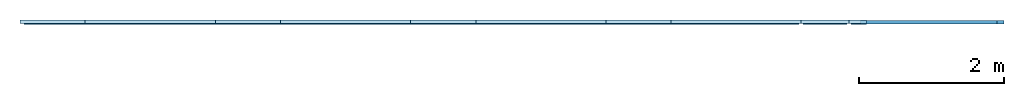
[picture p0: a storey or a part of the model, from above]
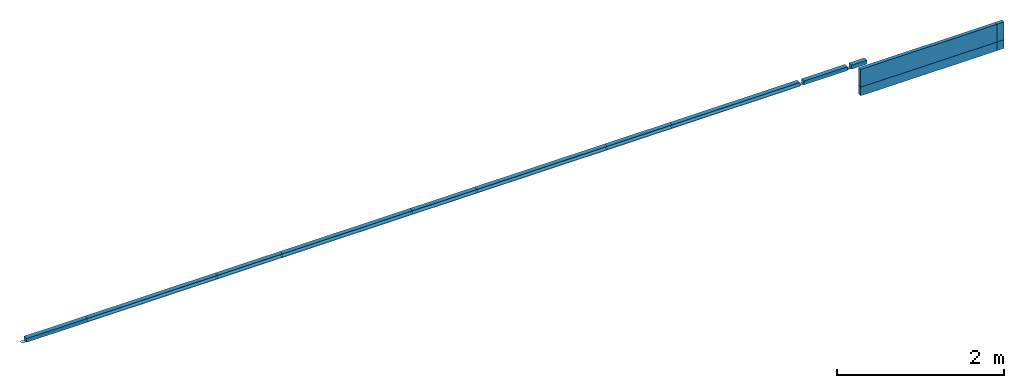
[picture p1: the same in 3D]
Properties of the parts of a building model (IFC2X3), part 1 of 2

# File
Description: ViewDefinition [CoordinationView]
File name: VA006-350-201.1.IFC (Edited by Naviate Simple BIM 2022 version 6)
Time: 2026-03-20T14:24:25+01:00
Written by: ODA SDAI 22.12
Made in: Autodesk Revit 23.1.90.15 (ENU) - IFC 23.3.1.0

# IfcProject
LongName: Trondheim Lufthavn Værnes; Phase: TU 2013

# IfcSite, Default
RefLatitude: 59, 54, 57, 601318; RefLongitude: 10, 44, 59, 999999; RefElevation: 0 mm
Identity Data - Workset: Project Info
Text - 01_Modellfil: va006-a-220-1-0001.rvt
Data - Ideate BIMLink: <?xml version="1.0" encoding="utf-8"?><application version="3"> <links> <link> <name>Casework Types</name> <description></description> <elements>CaseworkTypes</elements> <phase>Fase 2</phase> <phase_filter>None</phase_filter> <properties> <property> <name>Id</name> <lookup_1_type></lookup_1_type> <lookup_1_id></lookup_1_id> <type>BUILT_IN_PARAMETER</type> <id>ID_PARAM</id> </property> <property> <name>Family Name</name> <lookup_1_type></lookup_1_type> <lookup_1_id></lookup_1_id> <type>CALCULATED_PROPERTY</type> <id>FamilyName</id> </property> <property> <name>Type Name</name> <lookup_1_type></lookup_1_type> <lookup_1_id></lookup_1_id> <type>CALCULATED_PROPERTY</type> <id>TypeName</id> </property> </properties> </link> <link> <name>Window Types</name> <description></description> <elements>WindowTypes</elements> <phase>Fase 2</phase> <phase_filter>None</phase_filter> <properties> <property> <name>Id</name> <lookup_1_type></lookup_1_type> <lookup_1_id></lookup_1_id> <type>BUILT_IN_PARAMETER</type> <id>ID_PARAM</id> </property> <property> <name>Family Name</name> <lookup_1_type></lookup_1_type> <lookup_1_id></lookup_1_id> <type>CALCULATED_PROPERTY</type> <id>FamilyName</id> </property> <property> <name>Type Name</name> <lookup_1_type></lookup_1_type> <lookup_1_id></lookup_1_id> <type>CALCULATED_PROPERTY</type> <id>TypeName</id> </property> </properties> </link> <link> <name>Wall Types</name> <description></description> <elements>WallTypes</elements> <phase>Fase 1</phase> <phase_filter>Show Complete</phase_filter> <properties> <property> <name>Id</name> <lookup_1_type></lookup_1_type> <lookup_1_id></lookup_1_id> <type>BUILT_IN_PARAMETER</type> <id>ID_PARAM</id> </property> <property> <name>Family Name</name> <lookup_1_type></lookup_1_type> <lookup_1_id></lookup_1_id> <type>BUILT_IN_PARAMETER</type> <id>SYMBOL_FAMILY_NAME_PARAM</id> </property> <property> <name>Type Name</name> <lookup_1_type></lookup_1_type> <lookup_1_id></lookup_1_id> <type>CALCULATED_PROPERTY</type> <id>TypeName</id> </property> </properties> </link> <link> <name>Structural Framing Types</name> <description></description> <elements>StructuralFramingTypes</elements> <phase>Fase 2</phase> <phase_filter>None</phase_filter> <properties> <property> <name>Id</name> <lookup_1_type></lookup_1_type> <lookup_1_id></lookup_1_id> <type>BUILT_IN_PARAMETER</type> <id>ID_PARAM</id> </property> <property> <name>Family Name</name> <lookup_1_type></lookup_1_type> <lookup_1_id></lookup_1_id> <type>CALCULATED_PROPERTY</type> <id>FamilyName</id> </property> <property> <name>Type Name</name> <lookup_1_type></lookup_1_type> <lookup_1_id></lookup_1_id> <type>CALCULATED_PROPERTY</type> <id>TypeName</id> </property> </properties> </link> <link> <name>Structural Foundation Types</name> <description></description> <elements>StructuralFoundationTypes</elements> <phase>Fase 2</phase> <phase_filter>None</phase_filter> <properties> <property> <name>Id</name> <lookup_1_type></lookup_1_type> <lookup_1_id></lookup_1_id> <type>BUILT_IN_PARAMETER</type> <id>ID_PARAM</id> </property> <property> <name>Family Name</name> <lookup_1_type></lookup_1_type> <lookup_1_id></lookup_1_id> <type>CALCULATED_PROPERTY</type> <id>FamilyName</id> </property> <property> <name>Type Name</name> <lookup_1_type></lookup_1_type> <lookup_1_id></lookup_1_id> <type>CALCULATED_PROPERTY</type> <id>TypeName</id> </property> </properties> </link> <link> <name>Structural Column Types</name> <description></description> <elements>StructuralColumnTypes</elements> <phase>Fase 2</phase> <phase_filter>None</phase_filter> <properties> <property> <name>Id</name> <lookup_1_type></lookup_1_type> <lookup_1_id></lookup_1_id> <type>BUILT_IN_PARAMETER</type> <id>ID_PARAM</id> </property> <property> <name>Family Name</name> <lookup_1_type></lookup_1_type> <lookup_1_id></lookup_1_id> <type>CALCULATED_PROPERTY</type> <id>FamilyName</id> </property> <property> <name>Type Name</name> <lookup_1_type></lookup_1_type> <lookup_1_id></lookup_1_id> <type>CALCULATED_PROPERTY</type> <id>TypeName</id> </property> </properties> </link> <link> <name>Stair Types</name> <description></description> <elements>StairTypes</elements> <phase>Fase 2</phase> <phase_filter>None</phase_filter> <properties> <property> <name>Id</name> <lookup_1_type></lookup_1_type> <lookup_1_id></lookup_1_id> <type>BUILT_IN_PARAMETER</type> <id>ID_PARAM</id> </property> <property> <name>Family Name</name> <lookup_1_type></lookup_1_type> <lookup_1_id></lookup_1_id> <type>BUILT_IN_PARAMETER</type> <id>ALL_MODEL_FAMILY_NAME</id> </property> <property> <name>Type Name</name> <lookup_1_type></lookup_1_type> <lookup_1_id></lookup_1_id> <type>CALCULATED_PROPERTY</type> <id>TypeName</id> </property> </properties> </link> <link> <name>Specialty Equipment Types</name> <description></description> <elements>SpecialtyEquipmentTypes</elements> <phase>Fase 2</phase> <phase_filter>None</phase_filter> <properties> <property> <name>Id</name> <lookup_1_type></lookup_1_type> <lookup_1_id></lookup_1_id> <type>BUILT_IN_PARAMETER</type> <id>ID_PARAM</id> </property> <property> <name>Family Name</name> <lookup_1_type></lookup_1_type> <lookup_1_id></lookup_1_id> <type>CALCULATED_PROPERTY</type> <id>FamilyName</id> </property> <property> <name>Type Name</name> <lookup_1_type></lookup_1_type> <lookup_1_id></lookup_1_id> <type>CALCULATED_PROPERTY</type> <id>TypeName</id> </property> </properties> </link> <link> <name>Roof Types</name> <description></description> <elements>RoofTypes</elements> <phase>Fase 2</phase> <phase_filter>None</phase_filter> <properties> <property> <name>Id</name> <lookup_1_type></lookup_1_type> <lookup_1_id></lookup_1_id> <type>BUILT_IN_PARAMETER</type> <id>ID_PARAM</id> </property> <property> <name>Family Name</name> <lookup_1_type></lookup_1_type> <lookup_1_id></lookup_1_id> <type>BUILT_IN_PARAMETER</type> <id>ALL_MODEL_FAMILY_NAME</id> </property> <property> <name>Type Name</name> <lookup_1_type></lookup_1_type> <lookup_1_id></lookup_1_id> <type>CALCULATED_PROPERTY</type> <id>TypeName</id> </property> </properties> </link> <link> <name>Ramp Types</name> <description></description> <elements>RampTypes</elements> <phase>Fase 2</phase> <phase_filter>None</phase_filter> <properties> <property> <name>Id</name> <lookup_1_type></lookup_1_type> <lookup_1_id></lookup_1_id> <type>BUILT_IN_PARAMETER</type> <id>ID_PARAM</id> </property> <property> <name>Family Name</name> <lookup_1_type></lookup_1_type> <lookup_1_id></lookup_1_id> <type>BUILT_IN_PARAMETER</type> <id>ALL_MODEL_FAMILY_NAME</id> </property> <property> <name>Type Name</name> <lookup_1_type></lookup_1_type> <lookup_1_id></lookup_1_id> <type>CALCULATED_PROPERTY</type> <id>TypeName</id> </property> </properties> </link> <link> <name>Railing Types</name> <description></description> <elements>RailingTypes</elements> <phase>Fase 2</phase> <phase_filter>None</phase_filter> <properties> <property> <name>Id</name> <lookup_1_type></lookup_1_type> <lookup_1_id></lookup_1_id> <type>BUILT_IN_PARAMETER</type> <id>ID_PARAM</id> </property> <property> <name>Family Name</name> <lookup_1_type></lookup_1_type> <lookup_1_id></lookup_1_id> <type>BUILT_IN_PARAMETER</type> <id>ALL_MODEL_FAMILY_NAME</id> </property> <property> <name>Type Name</name> <lookup_1_type></lookup_1_type> <lookup_1_id></lookup_1_id> <type>CALCULATED_PROPERTY</type> <id>TypeName</id> </property> </properties> </link> <link> <name>Profile Types</name> <description></description> <elements>ProfileTypes</elements> <phase>Fase 2</phase> <phase_filter>None</phase_filter> <properties> <property> <name>Id</name> <lookup_1_type></lookup_1_type> <lookup_1_id></lookup_1_id> <type>BUILT_IN_PARAMETER</type> <id>ID_PARAM</id> </property> <property> <name>Family Name</name> <lookup_1_type></lookup_1_type> <lookup_1_id></lookup_1_id> <type>BUILT_IN_PARAMETER</type> <id>ALL_MODEL_FAMILY_NAME</id> </property> <property> <name>Type Name</name> <lookup_1_type></lookup_1_type> <lookup_1_id></lookup_1_id> <type>CALCULATED_PROPERTY</type> <id>TypeName</id> </property> </properties> </link> <link> <name>Plumbing Fixture Types</name> <description></description> <elements>PlumbingFixtureTypes</elements> <phase>Fase 2</phase> <phase_filter>None</phase_filter> <properties> <property> <name>Id</name> <lookup_1_type></lookup_1_type> <lookup_1_id></lookup_1_id> <type>BUILT_IN_PARAMETER</type> <id>ID_PARAM</id> </property> <property> <name>Family Name</name> <lookup_1_type></lookup_1_type> <lookup_1_id></lookup_1_id> <type>CALCULATED_PROPERTY</type> <id>FamilyName</id> </property> <property> <name>Type Name</name> <lookup_1_type></lookup_1_type> <lookup_1_id></lookup_1_id> <type>CALCULATED_PROPERTY</type> <id>TypeName</id> </property> </properties> </link> <link> <name>Mechanical Equipment Types</name> <description></description> <elements>MechanicalEquipmentTypes</elements> <phase>Fase 2</phase> <phase_filter>None</phase_filter> <properties> <property> <name>Id</name> <lookup_1_type></lookup_1_type> <lookup_1_id></lookup_1_id> <type>BUILT_IN_PARAMETER</type> <id>ID_PARAM</id> </property> <property> <name>Family Name</name> <lookup_1_type></lookup_1_type> <lookup_1_id></lookup_1_id> <type>CALCULATED_PROPERTY</type> <id>FamilyName</id> </property> <property> <name>Type Name</name> <lookup_1_type></lookup_1_type> <lookup_1_id></lookup_1_id> <type>CALCULATED_PROPERTY</type> <id>TypeName</id> </property> </properties> </link> <link> <name>Mass Types</name> <description></description> <elements>MassTypes</elements> <phase>Fase 2</phase> <phase_filter>None</phase_filter> <properties> <property> <name>Id</name> <lookup_1_type></lookup_1_type> <lookup_1_id></lookup_1_id> <type>BUILT_IN_PARAMETER</type> <id>ID_PARAM</id> </property> <property> <name>Family Name</name> <lookup_1_type></lookup_1_type> <lookup_1_id></lookup_1_id> <type>CALCULATED_PROPERTY</type> <id>FamilyName</id> </property> <property> <name>Type Name</name> <lookup_1_type></lookup_1_type> <lookup_1_id></lookup_1_id> <type>CALCULATED_PROPERTY</type> <id>TypeName</id> </property> </properties> </link> <link> <name>Generic Model Types</name> <description></description> <elements>GenericModelTypes</elements> <phase>Fase 2</phase> <phase_filter>None</phase_filter> <properties> <property> <name>Id</name> <lookup_1_type></lookup_1_type> <lookup_1_id></lookup_1_id> <type>BUILT_IN_PARAMETER</type> <id>ID_PARAM</id> </property> <property> <name>Family Name</name> <lookup_1_type></lookup_1_type> <lookup_1_id></lookup_1_id> <type>CALCULATED_PROPERTY</type> <id>FamilyName</id> </property> <property> <name>Type Name</name> <lookup_1_type></lookup_1_type> <lookup_1_id></lookup_1_id> <type>CALCULATED_PROPERTY</type> <id>TypeName</id> </property> </properties> </link> <link> <name>Column Types</name> <description></description> <elements>ColumnTypes</elements> <phase>Fase 2</phase> <phase_filter>None</phase_filter> <properties> <property> <name>Id</name> <lookup_1_type></lookup_1_type> <lookup_1_id></lookup_1_id> <type>BUILT_IN_PARAMETER</type> <id>ID_PARAM</id> </property> <property> <name>Family Name</name> <lookup_1_type></lookup_1_type> <lookup_1_id></lookup_1_id> <type>CALCULATED_PROPERTY</type> <id>FamilyName</id> </property> <property> <name>Type Name</name> <lookup_1_type></lookup_1_type> <lookup_1_id></lookup_1_id> <type>CALCULATED_PROPERTY</type> <id>TypeName</id> </property> </properties> </link> <link> <name>Columns</name> <description></description> <elements>ColumnInstances</elements> <phase>Fase 2</phase> <phase_filter>None</phase_filter> <properties> <property> <name>Id</name> <lookup_1_type></lookup_1_type> <lookup_1_id></lookup_1_id> <type>BUILT_IN_PARAMETER</type> <id>ID_PARAM</id> </property> </properties> </link> <link> <name>Door Types</name> <description></description> <elements>DoorTypes</elements> <phase>Fase 2</phase> <phase_filter>None</phase_filter> <properties> <property> <name>Id</name> <lookup_1_type></lookup_1_type> <lookup_1_id></lookup_1_id> <type>BUILT_IN_PARAMETER</type> <id>ID_PARAM</id> </property> <property> <name>Family Name</name> <lookup_1_type></lookup_1_type> <lookup_1_id></lookup_1_id> <type>CALCULATED_PROPERTY</type> <id>FamilyName</id> </property> <property> <name>Type Name</name> <lookup_1_type></lookup_1_type> <lookup_1_id></lookup_1_id> <type>CALCULATED_PROPERTY</type> <id>TypeName</id> </property> </properties> </link> <link> <name>Door Types 2</name> <description></description> <elements>DoorTypes</elements> <phase>Fase 1</phase> <phase_filter>Show Complete</phase_filter> <properties> <property> <name>Id</name> <lookup_1_type></lookup_1_type> <lookup_1_id></lookup_1_id> <type>BUILT_IN_PARAMETER</type> <id>ID_PARAM</id> </property> <property> <name>Family Name</name> <lookup_1_type></lookup_1_type> <lookup_1_id></lookup_1_id> <type>CALCULATED_PROPERTY</type> <id>FamilyName</id> </property> <property> <name>Type Name</name> <lookup_1_type></lookup_1_type> <lookup_1_id></lookup_1_id> <type>CALCULATED_PROPERTY</type> <id>TypeName</id> </property> </properties> </link> <link> <name>Ceiling Types</name> <description></description> <elements>CeilingTypes</elements> <phase>Fase 2</phase> <phase_filter>None</phase_filter> <properties> <property> <name>Id</name> <lookup_1_type></lookup_1_type> <lookup_1_id></lookup_1_id> <type>BUILT_IN_PARAMETER</type> <id>ID_PARAM</id> </property> <property> <name>Family Name</name> <lookup_1_type></lookup_1_type> <lookup_1_id></lookup_1_id> <type>BUILT_IN_PARAMETER</type> <id>ALL_MODEL_FAMILY_NAME</id> </property> <property> <name>Type Name</name> <lookup_1_type></lookup_1_type> <lookup_1_id></lookup_1_id> <type>CALCULATED_PROPERTY</type> <id>TypeName</id> </property> </properties> </link> <link> <name>Ceilings</name> <description></description> <elements>CeilingInstances</elements> <phase>Fase 2</phase> <phase_filter>None</phase_filter> <properties> <property> <name>Id</name> <lookup_1_type></lookup_1_type> <lookup_1_id></lookup_1_id> <type>BUILT_IN_PARAMETER</type> <id>ID_PARAM</id> </property> <property> <name>Family Name</name> <lookup_1_type>BUILT_IN_PARAMETER</lookup_1_type> <lookup_1_id>SYMBOL_ID_PARAM</lookup_1_id> <type>BUILT_IN_PARAMETER</type> <id>ALL_MODEL_FAMILY_NAME</id> </property> <property> <name>Type Name</name> <lookup_1_type>BUILT_IN_PARAMETER</lookup_1_type> <lookup_1_id>SYMBOL_ID_PARAM</lookup_1_id> <type>CALCULATED_PROPERTY</type> <id>TypeName</id> </property> </properties> </link> <link> <name>Furniture Types</name> <description></description> <elements>FurnitureTypes</elements> <phase>Fase 2</phase> <phase_filter>None</phase_filter> <properties> <property> <name>Id</name> <lookup_1_type></lookup_1_type> <lookup_1_id></lookup_1_id> <type>BUILT_IN_PARAMETER</type> <id>ID_PARAM</id> </property> <property> <name>Family Name</name> <lookup_1_type></lookup_1_type> <lookup_1_id></lookup_1_id> <type>CALCULATED_PROPERTY</type> <id>FamilyName</id> </property> <property> <name>Type Name</name> <lookup_1_type></lookup_1_type> <lookup_1_id></lookup_1_id> <type>CALCULATED_PROPERTY</type> <id>TypeName</id> </property> </properties> </link> <link> <name>Furniture System Types</name> <description></description> <elements>FurnitureSystemTypes</elements> <phase>Fase 2</phase> <phase_filter>None</phase_filter> <properties> <property> <name>Id</name> <lookup_1_type></lookup_1_type> <lookup_1_id></lookup_1_id> <type>BUILT_IN_PARAMETER</type> <id>ID_PARAM</id> </property> <property> <name>Family Name</name> <lookup_1_type></lookup_1_type> <lookup_1_id></lookup_1_id> <type>CALCULATED_PROPERTY</type> <id>FamilyName</id> </property> <property> <name>Type Name</name> <lookup_1_type></lookup_1_type> <lookup_1_id></lookup_1_id> <type>CALCULATED_PROPERTY</type> <id>TypeName</id> </property> </properties> </link> <link> <name>Sheets</name> <description></description> <elements>Sheets</elements> <phase>Fase 1</phase> <phase_filter>None</phase_filter> <properties> <property> <name>Id</name> <lookup_1_type></lookup_1_type> <lookup_1_id></lookup_1_id> <type>BUILT_IN_PARAMETER</type> <id>ID_PARAM</id> </property> </properties> </link> <link> <name>Walls</name> <description></description> <elements>WallInstances</elements> <phase>Fase 2</phase> <phase_filter>None</phase_filter> <properties> <property> <name>Id</name> <lookup_1_type></lookup_1_type> <lookup_1_id></lookup_1_id> <type>BUILT_IN_PARAMETER</type> <id>ID_PARAM</id> </property> </properties> </link> <link> <name>Wall types all official names</name> <description></description> <elements>WallTypes</elements> <phase>Fase 1</phase> <phase_filter>None</phase_filter> <properties> <property> <name>Id</name> <lookup_1_type></lookup_1_type> <lookup_1_id></lookup_1_id> <type>BUILT_IN_PARAMETER</type> <id>ID_PARAM</id> </property> <property> <name>Family Name</name> <lookup_1_type></lookup_1_type> <lookup_1_id></lookup_1_id> <type>BUILT_IN_PARAMETER</type> <id>ALL_MODEL_FAMILY_NAME</id> </property> <property> <name>Type Name</name> <lookup_1_type></lookup_1_type> <lookup_1_id></lookup_1_id> <type>CALCULATED_PROPERTY</type> <id>TypeName</id> </property> </properties> </link> <link> <name>test</name> <description></description> <elements>WallTypes</elements> <phase>Fase 1</phase> <phase_filter>None</phase_filter> <properties> <property> <name>Id</name> <lookup_1_type></lookup_1_type> <lookup_1_id></lookup_1_id> <type>BUILT_IN_PARAMETER</type> <id>ID_PARAM</id> </property> <property> <name>Family Name</name> <lookup_1_type></lookup_1_type> <lookup_1_id></lookup_1_id> <type>BUILT_IN_PARAMETER</type> <id>ALL_MODEL_FAMILY_NAME</id> </property> <property> <name>Type Name</name> <lookup_1_type></lookup_1_type> <lookup_1_id></lookup_1_id> <type>CALCULATED_PROPERTY</type> <id>TypeName</id> </property> </properties> </link> </links></application>
Other - RIE, firma: RAMBØLL AS; Project Status: TU 2013; Saksbehandler: MR; Project Address: Skriv adresse her; Category: Project Information; Prosjektansvarlig: TILBUD E203 TETT BYGG; RIV, telefon: +47 7310 6200; RIB, telefon: +47 7289 3750; Project Name: Trondheim Lufthavn Værnes; RIV, firma: MULTICONSULT AS; RIB, firma: NORCONSULT; RIE, telefon: +47 7389 1000

# IfcBuilding
Pset_BuildingCommon - NumberOfStoreys: 7
Identity Data - Workset: Project Info
Text - 01_Modellfil: va006-a-220-1-0001.rvt
Data - Ideate BIMLink: <?xml version="1.0" encoding="utf-8"?><application version="3"> <links> <link> <name>Casework Types</name> <description></description> <elements>CaseworkTypes</elements> <phase>Fase 2</phase> <phase_filter>None</phase_filter> <properties> <property> <name>Id</name> <lookup_1_type></lookup_1_type> <lookup_1_id></lookup_1_id> <type>BUILT_IN_PARAMETER</type> <id>ID_PARAM</id> </property> <property> <name>Family Name</name> <lookup_1_type></lookup_1_type> <lookup_1_id></lookup_1_id> <type>CALCULATED_PROPERTY</type> <id>FamilyName</id> </property> <property> <name>Type Name</name> <lookup_1_type></lookup_1_type> <lookup_1_id></lookup_1_id> <type>CALCULATED_PROPERTY</type> <id>TypeName</id> </property> </properties> </link> <link> <name>Window Types</name> <description></description> <elements>WindowTypes</elements> <phase>Fase 2</phase> <phase_filter>None</phase_filter> <properties> <property> <name>Id</name> <lookup_1_type></lookup_1_type> <lookup_1_id></lookup_1_id> <type>BUILT_IN_PARAMETER</type> <id>ID_PARAM</id> </property> <property> <name>Family Name</name> <lookup_1_type></lookup_1_type> <lookup_1_id></lookup_1_id> <type>CALCULATED_PROPERTY</type> <id>FamilyName</id> </property> <property> <name>Type Name</name> <lookup_1_type></lookup_1_type> <lookup_1_id></lookup_1_id> <type>CALCULATED_PROPERTY</type> <id>TypeName</id> </property> </properties> </link> <link> <name>Wall Types</name> <description></description> <elements>WallTypes</elements> <phase>Fase 1</phase> <phase_filter>Show Complete</phase_filter> <properties> <property> <name>Id</name> <lookup_1_type></lookup_1_type> <lookup_1_id></lookup_1_id> <type>BUILT_IN_PARAMETER</type> <id>ID_PARAM</id> </property> <property> <name>Family Name</name> <lookup_1_type></lookup_1_type> <lookup_1_id></lookup_1_id> <type>BUILT_IN_PARAMETER</type> <id>SYMBOL_FAMILY_NAME_PARAM</id> </property> <property> <name>Type Name</name> <lookup_1_type></lookup_1_type> <lookup_1_id></lookup_1_id> <type>CALCULATED_PROPERTY</type> <id>TypeName</id> </property> </properties> </link> <link> <name>Structural Framing Types</name> <description></description> <elements>StructuralFramingTypes</elements> <phase>Fase 2</phase> <phase_filter>None</phase_filter> <properties> <property> <name>Id</name> <lookup_1_type></lookup_1_type> <lookup_1_id></lookup_1_id> <type>BUILT_IN_PARAMETER</type> <id>ID_PARAM</id> </property> <property> <name>Family Name</name> <lookup_1_type></lookup_1_type> <lookup_1_id></lookup_1_id> <type>CALCULATED_PROPERTY</type> <id>FamilyName</id> </property> <property> <name>Type Name</name> <lookup_1_type></lookup_1_type> <lookup_1_id></lookup_1_id> <type>CALCULATED_PROPERTY</type> <id>TypeName</id> </property> </properties> </link> <link> <name>Structural Foundation Types</name> <description></description> <elements>StructuralFoundationTypes</elements> <phase>Fase 2</phase> <phase_filter>None</phase_filter> <properties> <property> <name>Id</name> <lookup_1_type></lookup_1_type> <lookup_1_id></lookup_1_id> <type>BUILT_IN_PARAMETER</type> <id>ID_PARAM</id> </property> <property> <name>Family Name</name> <lookup_1_type></lookup_1_type> <lookup_1_id></lookup_1_id> <type>CALCULATED_PROPERTY</type> <id>FamilyName</id> </property> <property> <name>Type Name</name> <lookup_1_type></lookup_1_type> <lookup_1_id></lookup_1_id> <type>CALCULATED_PROPERTY</type> <id>TypeName</id> </property> </properties> </link> <link> <name>Structural Column Types</name> <description></description> <elements>StructuralColumnTypes</elements> <phase>Fase 2</phase> <phase_filter>None</phase_filter> <properties> <property> <name>Id</name> <lookup_1_type></lookup_1_type> <lookup_1_id></lookup_1_id> <type>BUILT_IN_PARAMETER</type> <id>ID_PARAM</id> </property> <property> <name>Family Name</name> <lookup_1_type></lookup_1_type> <lookup_1_id></lookup_1_id> <type>CALCULATED_PROPERTY</type> <id>FamilyName</id> </property> <property> <name>Type Name</name> <lookup_1_type></lookup_1_type> <lookup_1_id></lookup_1_id> <type>CALCULATED_PROPERTY</type> <id>TypeName</id> </property> </properties> </link> <link> <name>Stair Types</name> <description></description> <elements>StairTypes</elements> <phase>Fase 2</phase> <phase_filter>None</phase_filter> <properties> <property> <name>Id</name> <lookup_1_type></lookup_1_type> <lookup_1_id></lookup_1_id> <type>BUILT_IN_PARAMETER</type> <id>ID_PARAM</id> </property> <property> <name>Family Name</name> <lookup_1_type></lookup_1_type> <lookup_1_id></lookup_1_id> <type>BUILT_IN_PARAMETER</type> <id>ALL_MODEL_FAMILY_NAME</id> </property> <property> <name>Type Name</name> <lookup_1_type></lookup_1_type> <lookup_1_id></lookup_1_id> <type>CALCULATED_PROPERTY</type> <id>TypeName</id> </property> </properties> </link> <link> <name>Specialty Equipment Types</name> <description></description> <elements>SpecialtyEquipmentTypes</elements> <phase>Fase 2</phase> <phase_filter>None</phase_filter> <properties> <property> <name>Id</name> <lookup_1_type></lookup_1_type> <lookup_1_id></lookup_1_id> <type>BUILT_IN_PARAMETER</type> <id>ID_PARAM</id> </property> <property> <name>Family Name</name> <lookup_1_type></lookup_1_type> <lookup_1_id></lookup_1_id> <type>CALCULATED_PROPERTY</type> <id>FamilyName</id> </property> <property> <name>Type Name</name> <lookup_1_type></lookup_1_type> <lookup_1_id></lookup_1_id> <type>CALCULATED_PROPERTY</type> <id>TypeName</id> </property> </properties> </link> <link> <name>Roof Types</name> <description></description> <elements>RoofTypes</elements> <phase>Fase 2</phase> <phase_filter>None</phase_filter> <properties> <property> <name>Id</name> <lookup_1_type></lookup_1_type> <lookup_1_id></lookup_1_id> <type>BUILT_IN_PARAMETER</type> <id>ID_PARAM</id> </property> <property> <name>Family Name</name> <lookup_1_type></lookup_1_type> <lookup_1_id></lookup_1_id> <type>BUILT_IN_PARAMETER</type> <id>ALL_MODEL_FAMILY_NAME</id> </property> <property> <name>Type Name</name> <lookup_1_type></lookup_1_type> <lookup_1_id></lookup_1_id> <type>CALCULATED_PROPERTY</type> <id>TypeName</id> </property> </properties> </link> <link> <name>Ramp Types</name> <description></description> <elements>RampTypes</elements> <phase>Fase 2</phase> <phase_filter>None</phase_filter> <properties> <property> <name>Id</name> <lookup_1_type></lookup_1_type> <lookup_1_id></lookup_1_id> <type>BUILT_IN_PARAMETER</type> <id>ID_PARAM</id> </property> <property> <name>Family Name</name> <lookup_1_type></lookup_1_type> <lookup_1_id></lookup_1_id> <type>BUILT_IN_PARAMETER</type> <id>ALL_MODEL_FAMILY_NAME</id> </property> <property> <name>Type Name</name> <lookup_1_type></lookup_1_type> <lookup_1_id></lookup_1_id> <type>CALCULATED_PROPERTY</type> <id>TypeName</id> </property> </properties> </link> <link> <name>Railing Types</name> <description></description> <elements>RailingTypes</elements> <phase>Fase 2</phase> <phase_filter>None</phase_filter> <properties> <property> <name>Id</name> <lookup_1_type></lookup_1_type> <lookup_1_id></lookup_1_id> <type>BUILT_IN_PARAMETER</type> <id>ID_PARAM</id> </property> <property> <name>Family Name</name> <lookup_1_type></lookup_1_type> <lookup_1_id></lookup_1_id> <type>BUILT_IN_PARAMETER</type> <id>ALL_MODEL_FAMILY_NAME</id> </property> <property> <name>Type Name</name> <lookup_1_type></lookup_1_type> <lookup_1_id></lookup_1_id> <type>CALCULATED_PROPERTY</type> <id>TypeName</id> </property> </properties> </link> <link> <name>Profile Types</name> <description></description> <elements>ProfileTypes</elements> <phase>Fase 2</phase> <phase_filter>None</phase_filter> <properties> <property> <name>Id</name> <lookup_1_type></lookup_1_type> <lookup_1_id></lookup_1_id> <type>BUILT_IN_PARAMETER</type> <id>ID_PARAM</id> </property> <property> <name>Family Name</name> <lookup_1_type></lookup_1_type> <lookup_1_id></lookup_1_id> <type>BUILT_IN_PARAMETER</type> <id>ALL_MODEL_FAMILY_NAME</id> </property> <property> <name>Type Name</name> <lookup_1_type></lookup_1_type> <lookup_1_id></lookup_1_id> <type>CALCULATED_PROPERTY</type> <id>TypeName</id> </property> </properties> </link> <link> <name>Plumbing Fixture Types</name> <description></description> <elements>PlumbingFixtureTypes</elements> <phase>Fase 2</phase> <phase_filter>None</phase_filter> <properties> <property> <name>Id</name> <lookup_1_type></lookup_1_type> <lookup_1_id></lookup_1_id> <type>BUILT_IN_PARAMETER</type> <id>ID_PARAM</id> </property> <property> <name>Family Name</name> <lookup_1_type></lookup_1_type> <lookup_1_id></lookup_1_id> <type>CALCULATED_PROPERTY</type> <id>FamilyName</id> </property> <property> <name>Type Name</name> <lookup_1_type></lookup_1_type> <lookup_1_id></lookup_1_id> <type>CALCULATED_PROPERTY</type> <id>TypeName</id> </property> </properties> </link> <link> <name>Mechanical Equipment Types</name> <description></description> <elements>MechanicalEquipmentTypes</elements> <phase>Fase 2</phase> <phase_filter>None</phase_filter> <properties> <property> <name>Id</name> <lookup_1_type></lookup_1_type> <lookup_1_id></lookup_1_id> <type>BUILT_IN_PARAMETER</type> <id>ID_PARAM</id> </property> <property> <name>Family Name</name> <lookup_1_type></lookup_1_type> <lookup_1_id></lookup_1_id> <type>CALCULATED_PROPERTY</type> <id>FamilyName</id> </property> <property> <name>Type Name</name> <lookup_1_type></lookup_1_type> <lookup_1_id></lookup_1_id> <type>CALCULATED_PROPERTY</type> <id>TypeName</id> </property> </properties> </link> <link> <name>Mass Types</name> <description></description> <elements>MassTypes</elements> <phase>Fase 2</phase> <phase_filter>None</phase_filter> <properties> <property> <name>Id</name> <lookup_1_type></lookup_1_type> <lookup_1_id></lookup_1_id> <type>BUILT_IN_PARAMETER</type> <id>ID_PARAM</id> </property> <property> <name>Family Name</name> <lookup_1_type></lookup_1_type> <lookup_1_id></lookup_1_id> <type>CALCULATED_PROPERTY</type> <id>FamilyName</id> </property> <property> <name>Type Name</name> <lookup_1_type></lookup_1_type> <lookup_1_id></lookup_1_id> <type>CALCULATED_PROPERTY</type> <id>TypeName</id> </property> </properties> </link> <link> <name>Generic Model Types</name> <description></description> <elements>GenericModelTypes</elements> <phase>Fase 2</phase> <phase_filter>None</phase_filter> <properties> <property> <name>Id</name> <lookup_1_type></lookup_1_type> <lookup_1_id></lookup_1_id> <type>BUILT_IN_PARAMETER</type> <id>ID_PARAM</id> </property> <property> <name>Family Name</name> <lookup_1_type></lookup_1_type> <lookup_1_id></lookup_1_id> <type>CALCULATED_PROPERTY</type> <id>FamilyName</id> </property> <property> <name>Type Name</name> <lookup_1_type></lookup_1_type> <lookup_1_id></lookup_1_id> <type>CALCULATED_PROPERTY</type> <id>TypeName</id> </property> </properties> </link> <link> <name>Column Types</name> <description></description> <elements>ColumnTypes</elements> <phase>Fase 2</phase> <phase_filter>None</phase_filter> <properties> <property> <name>Id</name> <lookup_1_type></lookup_1_type> <lookup_1_id></lookup_1_id> <type>BUILT_IN_PARAMETER</type> <id>ID_PARAM</id> </property> <property> <name>Family Name</name> <lookup_1_type></lookup_1_type> <lookup_1_id></lookup_1_id> <type>CALCULATED_PROPERTY</type> <id>FamilyName</id> </property> <property> <name>Type Name</name> <lookup_1_type></lookup_1_type> <lookup_1_id></lookup_1_id> <type>CALCULATED_PROPERTY</type> <id>TypeName</id> </property> </properties> </link> <link> <name>Columns</name> <description></description> <elements>ColumnInstances</elements> <phase>Fase 2</phase> <phase_filter>None</phase_filter> <properties> <property> <name>Id</name> <lookup_1_type></lookup_1_type> <lookup_1_id></lookup_1_id> <type>BUILT_IN_PARAMETER</type> <id>ID_PARAM</id> </property> </properties> </link> <link> <name>Door Types</name> <description></description> <elements>DoorTypes</elements> <phase>Fase 2</phase> <phase_filter>None</phase_filter> <properties> <property> <name>Id</name> <lookup_1_type></lookup_1_type> <lookup_1_id></lookup_1_id> <type>BUILT_IN_PARAMETER</type> <id>ID_PARAM</id> </property> <property> <name>Family Name</name> <lookup_1_type></lookup_1_type> <lookup_1_id></lookup_1_id> <type>CALCULATED_PROPERTY</type> <id>FamilyName</id> </property> <property> <name>Type Name</name> <lookup_1_type></lookup_1_type> <lookup_1_id></lookup_1_id> <type>CALCULATED_PROPERTY</type> <id>TypeName</id> </property> </properties> </link> <link> <name>Door Types 2</name> <description></description> <elements>DoorTypes</elements> <phase>Fase 1</phase> <phase_filter>Show Complete</phase_filter> <properties> <property> <name>Id</name> <lookup_1_type></lookup_1_type> <lookup_1_id></lookup_1_id> <type>BUILT_IN_PARAMETER</type> <id>ID_PARAM</id> </property> <property> <name>Family Name</name> <lookup_1_type></lookup_1_type> <lookup_1_id></lookup_1_id> <type>CALCULATED_PROPERTY</type> <id>FamilyName</id> </property> <property> <name>Type Name</name> <lookup_1_type></lookup_1_type> <lookup_1_id></lookup_1_id> <type>CALCULATED_PROPERTY</type> <id>TypeName</id> </property> </properties> </link> <link> <name>Ceiling Types</name> <description></description> <elements>CeilingTypes</elements> <phase>Fase 2</phase> <phase_filter>None</phase_filter> <properties> <property> <name>Id</name> <lookup_1_type></lookup_1_type> <lookup_1_id></lookup_1_id> <type>BUILT_IN_PARAMETER</type> <id>ID_PARAM</id> </property> <property> <name>Family Name</name> <lookup_1_type></lookup_1_type> <lookup_1_id></lookup_1_id> <type>BUILT_IN_PARAMETER</type> <id>ALL_MODEL_FAMILY_NAME</id> </property> <property> <name>Type Name</name> <lookup_1_type></lookup_1_type> <lookup_1_id></lookup_1_id> <type>CALCULATED_PROPERTY</type> <id>TypeName</id> </property> </properties> </link> <link> <name>Ceilings</name> <description></description> <elements>CeilingInstances</elements> <phase>Fase 2</phase> <phase_filter>None</phase_filter> <properties> <property> <name>Id</name> <lookup_1_type></lookup_1_type> <lookup_1_id></lookup_1_id> <type>BUILT_IN_PARAMETER</type> <id>ID_PARAM</id> </property> <property> <name>Family Name</name> <lookup_1_type>BUILT_IN_PARAMETER</lookup_1_type> <lookup_1_id>SYMBOL_ID_PARAM</lookup_1_id> <type>BUILT_IN_PARAMETER</type> <id>ALL_MODEL_FAMILY_NAME</id> </property> <property> <name>Type Name</name> <lookup_1_type>BUILT_IN_PARAMETER</lookup_1_type> <lookup_1_id>SYMBOL_ID_PARAM</lookup_1_id> <type>CALCULATED_PROPERTY</type> <id>TypeName</id> </property> </properties> </link> <link> <name>Furniture Types</name> <description></description> <elements>FurnitureTypes</elements> <phase>Fase 2</phase> <phase_filter>None</phase_filter> <properties> <property> <name>Id</name> <lookup_1_type></lookup_1_type> <lookup_1_id></lookup_1_id> <type>BUILT_IN_PARAMETER</type> <id>ID_PARAM</id> </property> <property> <name>Family Name</name> <lookup_1_type></lookup_1_type> <lookup_1_id></lookup_1_id> <type>CALCULATED_PROPERTY</type> <id>FamilyName</id> </property> <property> <name>Type Name</name> <lookup_1_type></lookup_1_type> <lookup_1_id></lookup_1_id> <type>CALCULATED_PROPERTY</type> <id>TypeName</id> </property> </properties> </link> <link> <name>Furniture System Types</name> <description></description> <elements>FurnitureSystemTypes</elements> <phase>Fase 2</phase> <phase_filter>None</phase_filter> <properties> <property> <name>Id</name> <lookup_1_type></lookup_1_type> <lookup_1_id></lookup_1_id> <type>BUILT_IN_PARAMETER</type> <id>ID_PARAM</id> </property> <property> <name>Family Name</name> <lookup_1_type></lookup_1_type> <lookup_1_id></lookup_1_id> <type>CALCULATED_PROPERTY</type> <id>FamilyName</id> </property> <property> <name>Type Name</name> <lookup_1_type></lookup_1_type> <lookup_1_id></lookup_1_id> <type>CALCULATED_PROPERTY</type> <id>TypeName</id> </property> </properties> </link> <link> <name>Sheets</name> <description></description> <elements>Sheets</elements> <phase>Fase 1</phase> <phase_filter>None</phase_filter> <properties> <property> <name>Id</name> <lookup_1_type></lookup_1_type> <lookup_1_id></lookup_1_id> <type>BUILT_IN_PARAMETER</type> <id>ID_PARAM</id> </property> </properties> </link> <link> <name>Walls</name> <description></description> <elements>WallInstances</elements> <phase>Fase 2</phase> <phase_filter>None</phase_filter> <properties> <property> <name>Id</name> <lookup_1_type></lookup_1_type> <lookup_1_id></lookup_1_id> <type>BUILT_IN_PARAMETER</type> <id>ID_PARAM</id> </property> </properties> </link> <link> <name>Wall types all official names</name> <description></description> <elements>WallTypes</elements> <phase>Fase 1</phase> <phase_filter>None</phase_filter> <properties> <property> <name>Id</name> <lookup_1_type></lookup_1_type> <lookup_1_id></lookup_1_id> <type>BUILT_IN_PARAMETER</type> <id>ID_PARAM</id> </property> <property> <name>Family Name</name> <lookup_1_type></lookup_1_type> <lookup_1_id></lookup_1_id> <type>BUILT_IN_PARAMETER</type> <id>ALL_MODEL_FAMILY_NAME</id> </property> <property> <name>Type Name</name> <lookup_1_type></lookup_1_type> <lookup_1_id></lookup_1_id> <type>CALCULATED_PROPERTY</type> <id>TypeName</id> </property> </properties> </link> <link> <name>test</name> <description></description> <elements>WallTypes</elements> <phase>Fase 1</phase> <phase_filter>None</phase_filter> <properties> <property> <name>Id</name> <lookup_1_type></lookup_1_type> <lookup_1_id></lookup_1_id> <type>BUILT_IN_PARAMETER</type> <id>ID_PARAM</id> </property> <property> <name>Family Name</name> <lookup_1_type></lookup_1_type> <lookup_1_id></lookup_1_id> <type>BUILT_IN_PARAMETER</type> <id>ALL_MODEL_FAMILY_NAME</id> </property> <property> <name>Type Name</name> <lookup_1_type></lookup_1_type> <lookup_1_id></lookup_1_id> <type>CALCULATED_PROPERTY</type> <id>TypeName</id> </property> </properties> </link> </links></application>
Other - RIE, firma: RAMBØLL AS; Project Status: TU 2013; Saksbehandler: MR; Project Address: Skriv adresse her; Category: Project Information; Prosjektansvarlig: TILBUD E203 TETT BYGG; RIV, telefon: +47 7310 6200; RIB, telefon: +47 7289 3750; Project Name: Trondheim Lufthavn Værnes; RIV, firma: MULTICONSULT AS; RIB, firma: NORCONSULT; RIE, telefon: +47 7389 1000

# IfcBuildingStorey: Level:JB + TC, +11.535 - TC/PIR - E1
LongName: +11.535 - TC/PIR - E1; Elevation: 11535 mm
Graphics(Type) - Line Pattern: Centre; Symbol: M_Level Head - Circle; Color: 0; Symbol at End 1 Default: yes; Symbol at End 2 Default: no; Line Weight: 4
Constraints - Elevation: 11535 mm
Identity Data - Name: +11.535 - TC/PIR - E1; Structural: no; Building Story: yes; AP3 PIR VEST: yes; Workset: Akser/Nivåer-AP3
Other - Type Id: 7724940; Type: JB + TC; Family and Type: Level: JB + TC; Category: Levels; Family: Level
Identity Data(Type) - Workset: Level Types; Type Name: JB + TC
Pset_ProductRequirements - Name: +11.535 - TC/PIR - E1; sets with these values: 2
Dimensions - Computation Height: 0 mm
Other(Type) - Category: Levels; Family Name: Level
Constraints(Type) - Elevation Base: Project Base Point

# IfcBuildingStorey: Level:TA (3)
Identity Data(Type) - Workset: Level Types; Type Name: TA
Graphics(Type) - Symbol: NSW Kote - Triangel med kote, ISO 2,5 mm (fault, do not use -DC) : NSW Kote - Triangel med kote, ISO 2,5 mm; Line Pattern: Centre; Color: 0; Symbol at End 1 Default: yes; Symbol at End 2 Default: no; Line Weight: 4
Other - Family and Type: Level: TA; Type Id: 7724934; Type: TA; Category: Levels; Family: Level
Identity Data - Structural: no; Building Story: yes; Workset: Shared Levels and Grids
Other(Type) - Category: Levels; Family Name: Level
Constraints(Type) - Elevation Base: Project Base Point
Name | LongName = Identity Data, Name | Elevation (mm) = Constraints, Elevation (mm) | Computation Height (mm) | Pset_ProductRequirements, Name | Pset_ProductRequirements, sets with these values
XX - C +10,75 TA E1 | XX - C +10,75 TA E1 | 10750 | 1200 | Pset_AirSideSystemInformation - Name: XX - C +10,75 TA E1; sets with these values: 2
XX - C +15,37 TA E2 | XX - C +15,37 TA E2 | 15370 | 1200 | XX - C +15,37 TA E2 | 2
XX - C +18,62 | XX - C +18,62 | 18620 | 0 | XX - C +18,62 | 2

# IfcCovering: Compound Ceiling:Værnes Himling H-SYS 01, Compound Ceiling:Værnes Himling H-SYS 01:18535406
In: XX - C +15,37 TA E2
Type - PredefinedType: CEILING
Type - Other - Category: Ceilings; Family Name: Compound Ceiling
Type - Construction - Thickness: 15 mm
Type - Graphics - Coarse Scale Fill Color: 0
Type - Identity Data - Type Name: Værnes Himling H-SYS 01; Workset: Ceiling Types
Type - Text - Himling Kode: H-SYS 01
Type - Analytical Properties - Roughness: 1; Absorptance: 0.1
Type - Pset_CoveringCommon - TotalThickness: 15 mm
Material: Structure - Light Gauge Steel Joist Layer 2 mm, _NSW Himlingsplate 600x600 mm 13 mm
Dimensions - Perimeter: 31225 mm; Volume: 0.569142 m3; Area: 37.9428 m2
ePset_Simplebim - Assembly Level: Leaf
ePset_LocationTool - Splitting: ORIGINAL
Constraints - Room Bounding: yes; Level: XX - C +15,37 TA E2; Height Offset From Level: 2415 mm
Other - Family: Compound Ceiling; Type: Værnes Himling H-SYS 01; Type Id: 6696750; Family and Type: Compound Ceiling: Værnes Himling H-SYS 01
Phasing - Phase Created: Som Bygget
Pset_QuantityTakeOff - Reference: Værnes Himling H-SYS 01
Pset_CoveringCommon - Reference: Værnes Himling H-SYS 01; Finish: _NSW Himlingsplate 600x600 mm;
Identity Data - TA Workset: yes; TB Workset: no; AP3 COMMUTER: no; Workset: XTB Terminal B
ePset_SimplebimBasicQuantities - Length (Simplebim): 12601.5 mm; Width (Simplebim): 3010.98 mm; Volume, net (Simplebim): 0.569142 m3; Area, largest surface, net (Simplebim): 37.9428 m2; Height (Simplebim): 15 mm

# IfcCurtainWall: Curtain Wall:V_Existing Curtain Wall, Curtain Wall:V_Existing Curtain Wall:5591690
In: XX - C +10,75 TA E1
Type - Other - Category: Walls; Family Name: Curtain Wall
Type - Construction - Function: Exterior; Automatically Embed: no; Join Condition: Not Defined
Type - Identity Data - Type Name: V_Existing Curtain Wall; Workset: Curtain Wall Types
Type - Horizontal Grid - Adjust for Mullion Size: no
Type - Vertical Grid - Adjust for Mullion Size: no
Type - Pset_CurtainWallCommon - IsExternal: yes
Phasing - Phase Created: Som Bygget
Pset_CurtainWallCommon - Reference: V_Existing Curtain Wall
ePset_Simplebim - Assembly Level: Topmost
Pset_QuantityTakeOff - Reference: V_Existing Curtain Wall
Structural - Structural Usage: Non-bearing; Structural: no
Other - Type: V_Existing Curtain Wall; Family and Type: Curtain Wall: V_Existing Curtain Wall; Type Id: 4351841; Family: Curtain Wall
Identity Data - TA Workset: yes; Workset: XTA Terminal A
Constraints - Base Constraint: XX - C +10,75 TA E1; Related to Mass: no; Base is Attached: no; Room Bounding: no; Top is Attached: no; Top Offset: 0 mm; Base Offset: 480 mm; Unconnected Height: 8190 mm
Cross-Section Definition - Cross-Section: Vertical
Dimensions - Area: 120.253 m2; Length: 33361.3 mm
Horizontal Grid - Angle: 0 deg; Offset: 0 mm; Number: 4; Justification: Beginning
Vertical Grid - Number: 4; Angle: 0 deg; Offset: 0 mm; Justification: Beginning
ePset_SimplebimBasicQuantities - Length: 33361.3 mm; Width: 296.5 mm; Height: 8190 mm; Volume, net (Simplebim): 6.16834 m3

# IfcCurtainWall: Curtain Wall:Værnes Innervegg 06_Glass - Please sort, Curtain Wall:Værnes Innervegg 06_Glass - Please sort:1253110
In: XX - C +10,75 TA E1
Type - Other - Category: Walls; Family Name: Curtain Wall
Type - Construction - Function: Interior; Automatically Embed: no; Join Condition: Not Defined
Type - Identity Data - Type Name: Værnes Innervegg 06_Glass - Please sort; Workset: Curtain Wall Types
Type - Horizontal Grid - Adjust for Mullion Size: no
Type - Vertical Grid - Adjust for Mullion Size: no
Type - Pset_CurtainWallCommon - IsExternal: no
Pset_CurtainWallCommon - Reference: Værnes Innervegg 06_Glass - Please sort
Phasing - Phase Created: Som Bygget
ePset_Simplebim - Assembly Level: Topmost
Other - Type: Værnes Innervegg 06_Glass - Please sort; Family and Type: Curtain Wall: Værnes Innervegg 06_Glass - Please sort; Type Id: 334; Family: Curtain Wall
Structural - Structural Usage: Non-bearing; Structural: no
Identity Data - TA Workset: yes; Workset: XTA Terminal A
Pset_QuantityTakeOff - Reference: Værnes Innervegg 06_Glass - Please sort
Dimensions - Length: 14615 mm; Area: 8.71697 m2
Cross-Section Definition - Cross-Section: Vertical
ePset_SimplebimBasicQuantities - Length: 11700 mm; Height: 745.04 mm; Volume, net (Simplebim): 0.435357 m3; Width: 62.5 mm
Horizontal Grid - Angle: 0 deg; Offset: 0 mm; Number: 4; Justification: Beginning
Vertical Grid - Number: 4; Angle: 0 deg; Offset: 0 mm; Justification: Beginning
Constraints - Unconnected Height: 1300 mm; Base Constraint: XX - C +10,75 TA E1; Related to Mass: no; Base is Attached: no; Room Bounding: yes; Top is Attached: no; Top Offset: 0 mm; Base Offset: 8000 mm

# IfcMember: Rectangular Mullion:Værnes 50 x 56 (10)
In: XX - C +10,75 TA E1
Type - PredefinedType: MULLION; Material: T2_Metal_Aluminium
Type - Other - Category: Curtain Wall Mullions; Family Name: Rectangular Mullion
Type - Constraints - Angle: 0 deg; Offset: 0 mm
Type - Construction - Corner Mullion: no; Position: Perpendicular to Face; Profile: Værnes_Rail profile : P_Rail profile Værnes; Thickness: 60 mm
Type - Dimensions - Width on side 1: 28 mm; Width on side 2: 28 mm
Type - Identity Data - Type Name: Værnes 50 x 56; Workset: Family : Curtain Wall Mullions : Rectangular Mullion
Type - Materials and Finishes - Material: T2_Metal_Aluminium
Type - Pset_MemberCommon - IsExternal: no
Pset_MemberCommon - Reference: Værnes 50 x 56
ePset_LocationTool - Splitting: ORIGINAL
Identity Data - Workset: XTA Terminal A
ePset_Simplebim - Assembly Level: Leaf
Other - Family: Rectangular Mullion; Type Id: 2562502; Host Id: 1253110; Family and Type: Rectangular Mullion: Værnes 50 x 56; Type: Værnes 50 x 56
ePset_SimplebimBasicQuantities - Width (Simplebim): 60 mm; Height (Simplebim): 56 mm
Constraints - Level: XX - C +10,75 TA E1
Phasing - Phase Created: Som Bygget
Pset_QuantityTakeOff - Reference: Værnes 50 x 56
Name (Rectangular Mullion:Værnes 50 x 56:...) | Span (mm) = Length (mm) | TA Workset | Weight, as steel (Simplebim) (kg) | Volume, net (Simplebim) (m3) | Length (Simplebim) (mm) | Area, sides, net (Simplebim) (m2) | Volume (m3) | Area (m2)
2704846 | 1800 | yes | 47.4768 | 0.006048 | 1800 | 0.42432 | 0.006048 | 0.21216
2704878 | 900 | yes | 23.7384 | 0.003024 | 900 | 0.21552 | 0.003024 | 0.10776
2704908 | 1800 | yes | 47.4768 | 0.006048 | 1800 | 0.42432 | 0.006048 | 0.21216
2705000 | 900 | yes | 23.7384 | 0.003024 | 900 | 0.21552 | 0.003024 | 0.10776
2705037 | 1800 | yes | 47.4768 | 0.006048 | 1800 | 0.42432 | 0.006048 | 0.21216
2705066 | 900 | yes | 23.7384 | 0.003024 | 900 | 0.21552 | 0.003024 | 0.10776
2705100 | 1768.67 | yes | 46.6504 | 0.00594272 | 1768.67 | 0.417051 | 0.00594272 | 0.208525
2705132 | 604 | yes | 15.9311 | 0.00202944 | 604 | 0.146848 | 0.00202944 | 0.073424
2705201 | 215.333 | yes | 5.67963 | 0.00072352 | 215.333 | 0.0566773 | 0.00072352 | 0.0283387
13814362 | 844 |  | 22.2575 | 0.00283535 | 843.855 | 0.202494 | 0.00283584 | 0.101264 | Identity Data - AP3 PIR VEST: yes

# IfcPlate: System Panel:Glazed-generic (14)
In: XX - C +10,75 TA E1
Type - PredefinedType: CURTAIN_PANEL; Material: Glass 01_jb
Type - Other - Category: Curtain Panels; Family Name: System Panel
Type - Constraints - Offset: 8.5 mm
Type - Dimensions - Thickness: 48 mm
Type - Identity Data - Type Name: Glazed-generic; Workset: Family : Curtain Panels : System Panel
Type - Materials and Finishes - Material: Glass 01_jb
Type - Analytical Properties - Analytic Construction: <None>; Define Thermal Properties by: Schematic Type
Type - Pset_PlateCommon - IsExternal: no
Identity Data - Workset: XTA Terminal A
Pset_PlateCommon - Reference: Glazed-generic
ePset_Simplebim - Assembly Level: Leaf
Other - Type: Glazed-generic; Family: System Panel; Type Id: 403254; Family and Type: System Panel: Glazed-generic
ePset_LocationTool - Splitting: ORIGINAL
Constraints - Level: XX - C +10,75 TA E1
Pset_QuantityTakeOff - Reference: Glazed-generic
Phasing - Phase Created: Som Bygget
Name (System Panel:Glazed-generic:...) | TA Workset | Volume, net (Simplebim) (m3) = Volume (m3) | Area, largest surface, net (Simplebim) (m2) | Weight, as steel (Simplebim) (kg) | Height (mm) | Width (mm) | Area (m2) | Host Id
1253112 | yes | 0.0000864 | 0.0432 | 0.67824 | 2 | 900 | 0.0018 | 1253110 | Identity Data - AP3 PIR VEST: yes; Text - Entreprisenummer: AP3
2704838 | yes | 0.0001728 | 0.0864 | 1.35648 | 2 | 1800 | 0.0036 | 1253110
2704871 | yes | 0.0000864 | 0.0432 | 0.67824 | 2 | 900 | 0.0018 | 1253110
2704902 | yes | 0.0001728 | 0.0864 | 1.35648 | 2 | 1800 | 0.0036 | 1253110
2704992 | yes | 0.0000864 | 0.0432 | 0.67824 | 2 | 900 | 0.0018 | 1253110
2705031 | yes | 0.0001728 | 0.0864 | 1.35648 | 2 | 1800 | 0.0036 | 1253110
2705059 | yes | 0.0000864 | 0.0432 | 0.67824 | 2 | 900 | 0.0018 | 1253110
2705094 | yes | 0.00017248 | 0.08624 | 1.35397 | 2 | 1796.67 | 0.00359333 | 1253110
2705122 | yes | 0.00006336 | 0.03168 | 0.497376 | 2 | 660 | 0.00132 | 1253110
2705191 | yes | 0.00002336 | 0.01168 | 0.183376 | 2 | 243.333 | 0.000486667 | 1253110
15150706 |  | 0.0115728 | 0.241101 | 90.8468 | 127.905 | 1885 | 0.241101 | 5591690
5591827 | yes | 0.000613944 | 0.0127905 | 4.81946 | 127.905 | 100 | 0.0127905 | 5591690
15150707 |  | 0.0235248 | 0.4901 | 184.67 | 260 | 1885 | 0.4901 | 5591690
5591828 | yes | 0.001248 | 0.026 | 9.7968 | 260 | 100 | 0.026 | 5591690

# IfcRoof: Basic Roof:Tak tilbygg 330mm, Basic Roof:Tak tilbygg 330mm:18535396
In: XX - C +15,37 TA E2
Material: Værnes_Isolasjon-Mineralull 150 mm, Værnes_TRP 130 mm, Værnes_HS-Metalpanel_hovedtak 50 mm
Dimensions - Slope: 0.0349208; Area: 62.653 m2; Thickness: 330 mm; Volume: 20.6755 m3
Phasing - Phase Created: Som Bygget
Identity Data - Workset: XTB Terminal B
ePset_SimplebimBasicQuantities - Height: 495.975 mm; Width: 4747.14 mm; Length: 13190 mm; Volume, net (Simplebim): 20.6755 m3
Construction - Rafter Cut: Plumb Cut; Fascia Depth: 0 mm; Maximum Ridge Height: 18487.5 mm
Constraints - Base Offset From Level: 2621.53 mm; Room Bounding: yes; Related to Mass: no; Cutoff Offset: 0 mm; Base Level: XX - C +15,37 TA E2
Other - Type Id: 18534859; Family and Type: Basic Roof: Tak tilbygg 330mm; Type: Tak tilbygg 330mm; Family: Basic Roof; Category: Roofs
Pset_QuantityTakeOff - Reference: Tak tilbygg 330mm
ePset_Simplebim - Assembly Level: Topmost
Pset_RoofCommon - ProjectedArea: 62.6148 m2; Reference: Tak tilbygg 330mm; IsExternal: yes; TotalArea: 62.653 m2

# IfcSlab: Basic Roof:Tak tilbygg 330mm, Basic Roof:Tak tilbygg 330mm:18535396
In: XX - C +15,37 TA E2
PredefinedType: ROOF; Material: Værnes_Isolasjon-Mineralull 150 mm, Værnes_TRP 130 mm, Værnes_HS-Metalpanel_hovedtak 50 mm
ePset_LocationTool - Splitting: ORIGINAL
ePset_Simplebim - Assembly Level: Leaf
Pset_ReinforcementBarPitchOfSlab - Reference: Tak tilbygg 330mm; sets with these values: 2
Pset_SlabCommon - Reference: Tak tilbygg 330mm; IsExternal: yes; PitchAngle: 2 deg
ePset_SimplebimBasicQuantities - Area, sides, net (Simplebim): 11.8457 m2; Area, top, net (Simplebim): 62.653 m2; Area, largest surface, net (Simplebim): 62.653 m2; Perimeter (Simplebim): 35896.4 mm; Thickness (Simplebim): 329.998 mm; Volume, net (Simplebim): 20.6755 m3

# IfcSlab: Floor:NSW Generic 350 mm, Floor:NSW Generic 350 mm:328248
In: XX - C +15,37 TA E2
Type - PredefinedType: FLOOR; Material: Værnes_Aluminium 70 mm, _NSW Betong 280 mm
Type - Other - Category: Floors; Family Name: Floor
Type - Construction - Default Thickness: 350 mm; Function: Interior
Type - Graphics - Coarse Scale Fill Color: 0
Type - Identity Data - Type Name: NSW Generic 350 mm; Workset: Floor Types
Type - Materials and Finishes - Structural Material: _NSW Betong
Type - Text - Gulv Code: -
Type - Analytical Properties - Absorptance: 0.1; Roughness: 1
Type - Pset_SlabCommon - IsExternal: no
Structural - Structural: no
Other - Family and Type: Floor: NSW Generic 350 mm; Type: NSW Generic 350 mm; Family: Floor; Type Id: 11533893
Phasing - Phase Created: Som Bygget
Pset_ReinforcementBarPitchOfSlab - Reference: NSW Generic 350 mm; sets with these values: 2
Pset_SlabCommon - Reference: NSW Generic 350 mm; LoadBearing: no
ePset_SimplebimBasicQuantities - Volume, net (Simplebim): 0.802902 m3; Area, largest surface, net (Simplebim): 4.74876 m2; Thickness (Simplebim): 350 mm; Area, top, net (Simplebim): 2.294 m2; Area, sides, net (Simplebim): 13.1419 m2; Perimeter (Simplebim): 37548.3 mm
ePset_LocationTool - Splitting: RESULT
ePset_Simplebim - Assembly Level: Leaf
Constraints - Room Bounding: yes; Related to Mass: no; Level: XX - C +15,37 TA E2
Identity Data - TA Workset: yes; Has Association: no; Workset: XTA Terminal A

# IfcSlab: Floor:Værnes Betong 350mm, Floor:Værnes Betong 350mm:18535378
In: XX - C +15,37 TA E2
Type - PredefinedType: FLOOR; Material: Værnes_Flis Existing_Pink 12 mm, Værnes_Betong 350 mm
Type - Other - Category: Floors; Family Name: Floor
Type - Construction - Default Thickness: 362 mm; Function: Interior
Type - Graphics - Coarse Scale Fill Color: 0
Type - Identity Data - Type Name: Værnes Betong 350mm; Workset: Floor Types
Type - Materials and Finishes - Structural Material: Værnes_Betong
Type - Text - Gulv Code: -
Type - Analytical Properties - Absorptance: 0.1; Roughness: 1
Type - Pset_SlabCommon - IsExternal: no
Structural - Structural: no
Phasing - Phase Created: Som Bygget
Identity Data - TA Workset: yes; Has Association: no; Workset: XTB Terminal B
Constraints - Room Bounding: no; Height Offset From Level: 0 mm; Related to Mass: no; Level: XX - C +15,37 TA E2
ePset_Simplebim - Assembly Level: Leaf
ePset_LocationTool - Splitting: ORIGINAL
Pset_QuantityTakeOff - Reference: Værnes Betong 350mm; sets with these values: 2
Pset_SlabCommon - LoadBearing: no; PitchAngle: 0 deg; Reference: Værnes Betong 350mm
Other - Family and Type: Floor: Værnes Betong 350mm; Type: Værnes Betong 350mm; Type Id: 212970; Family: Floor
ePset_SimplebimBasicQuantities - Area, sides, net (Simplebim): 13.2932 m2; Volume, net (Simplebim): 24.6075 m3; Area, top, net (Simplebim): 67.9765 m2; Area, largest surface, net (Simplebim): 67.9765 m2; Thickness (Simplebim): 362 mm; Perimeter (Simplebim): 36721.7 mm
Dimensions - Volume: 24.6075 m3; Perimeter: 36721.7 mm; Area: 67.9765 m2; Thickness: 362 mm; Elevation at Bottom Core: 15008 mm; Elevation at Bottom: 15008 mm; Elevation at Top Core: 15370 mm; Elevation at Top: 15370 mm

# IfcWall: Basic Wall:242_TC_1/50 GIPS, Basic Wall:242_TC_1/50 GIPS:14840794
In: +11.535 - TC/PIR - E1
Type - PredefinedType: STANDARD; Material: TC-hvit malt 2 mm, Værnes_Gipsplate 13 mm, Værnes_Stålstender, uisolert 50 mm
Type - Other - Category: Walls; Family Name: Basic Wall
Type - Construction - Function: Interior; Width: 65 mm; Wrapping at Inserts: Both
Type - Graphics - Coarse Scale Fill Color: 12632256
Type - Identity Data - Type Name: 242_TC_1/50 GIPS; Workset: Wall Types; Akustikk: 48 DB; Keynote: SE-1/150
Type - Materials and Finishes - Structural Material: Værnes_Stålstender, uisolert
Type - Analytical Properties - Roughness: 1; Absorptance: 0.1
Type - Pset_WallCommon - IsExternal: no; FireRating: E160 (A60)
Type - Text - Core Kode: SE-1/50
Type - Pset_ConcreteElementGeneral - FireRating: E160 (A60)
ePset_LocationTool - Splitting: RESULT
Pset_WallCommon - LoadBearing: no; ExtendToStructure: no; Reference: 242_TC_1/50 GIPS
Cross-Section Definition - Cross-Section: Vertical
Structural - Structural Usage: Non-bearing; Structural: no
Constraints - Top Constraint: Up to level: +15.505 - TC/PIR - E2; Base Constraint: +11.535 - TC/PIR - E1; Location Line: Finish Face: Exterior; Room Bounding: yes; Related to Mass: no; Base is Attached: no; Top is Attached: no
ePset_SimplebimBasicQuantities - Area, side, gross, average (Simplebim): 0.182975 m2; Area, side, net, average (Simplebim): 0.182975 m2; Area, largest surface, net (Simplebim): 0.182975 m2; Area, side, gross, smaller (Simplebim): 0.182975 m2; Area, side, net, larger (Simplebim): 0.182975 m2; Area, side, net, smaller (Simplebim): 0.182975 m2; Area, side, gross, larger (Simplebim): 0.182975 m2; Volume, net (Simplebim): 0.0118934 m3; Thickness (Simplebim): 66 mm; Length (Simplebim): 281 mm; Height (Simplebim): 650 mm; Area, side, gross, AABB (Simplebim): 0.18265 m2
ePset_Simplebim - Assembly Level: Leaf
Identity Data - AP3 PIR VEST: yes; TB Workset: no; Workset: XTC og XJB Jernbanestasjonen og commuter lounge
Pset_QuantityTakeOff - Reference: 242_TC_1/50 GIPS; sets with these values: 2
Phasing - Phase Created: Som Bygget
Other - Type Id: 15039009; Family: Basic Wall; Family and Type: Basic Wall: 242_TC_1/50 GIPS; Type: 242_TC_1/50 GIPS

# IfcWall: Basic Wall:242_TC_22/100 GIPS-GIPS, Basic Wall:242_TC_22/100 GIPS-GIPS:14840831
In: +11.535 - TC/PIR - E1
Type - PredefinedType: STANDARD; Material: Værnes_Malt 2 mm, Værnes_Gipsplate 13 mm, Værnes_Gipsplate 13 mm, Værnes_Stålstender 100 mm, Værnes_Gipsplate 13 mm, Værnes_Gipsplate 13 mm, Værnes_Malt 2 mm
Type - Other - Category: Walls; Family Name: Basic Wall
Type - Construction - Function: Interior; Width: 156 mm; Wrapping at Inserts: Both
Type - Graphics - Coarse Scale Fill Color: 12632256
Type - Identity Data - Type Name: 242_TC_22/100 GIPS-GIPS; Workset: Wall Types; Akustikk: 48 DB
Type - Materials and Finishes - Structural Material: Værnes_Stålstender
Type - Analytical Properties - Roughness: 1; Absorptance: 0.1
Type - Pset_WallCommon - IsExternal: no; FireRating: E160 (A60)
Type - Text - Core Kode: SE-22/100; Vegg Kode: IV12
Type - Pset_ConcreteElementGeneral - FireRating: E160 (A60)
Text - Brann krav: EI 120/A2-s1,d0 [A 120]
Cross-Section Definition - Cross-Section: Vertical
Other - Type Id: 9789580; Family: Basic Wall; Family and Type: Basic Wall: 242_TC_22/100 GIPS-GIPS; Type: 242_TC_22/100 GIPS-GIPS
Pset_ReinforcementBarPitchOfWall - Reference: 242_TC_22/100 GIPS-GIPS; sets with these values: 2
Structural - Structural Usage: Non-bearing; Structural: no
Constraints - Top Constraint: Up to level: +15.505 - TC/PIR - E2; Base Constraint: +11.535 - TC/PIR - E1; Location Line: Finish Face: Exterior; Room Bounding: yes; Related to Mass: no; Base is Attached: no; Top is Attached: no
ePset_SimplebimBasicQuantities - Volume, net (Simplebim): 0.0219531 m3; Area, side, gross, AABB (Simplebim): 0.1404 m2; Area, side, gross, average (Simplebim): 0.140725 m2; Area, largest surface, net (Simplebim): 0.140725 m2; Area, side, net, average (Simplebim): 0.140725 m2; Area, side, net, smaller (Simplebim): 0.140725 m2; Area, side, net, larger (Simplebim): 0.140725 m2; Area, side, gross, smaller (Simplebim): 0.140725 m2; Area, side, gross, larger (Simplebim): 0.140725 m2; Thickness (Simplebim): 156 mm; Length (Simplebim): 216 mm; Height (Simplebim): 650 mm
ePset_Simplebim - Assembly Level: Leaf
ePset_LocationTool - Splitting: RESULT
Identity Data - AP3 PIR VEST: yes; TB Workset: no; Workset: XTC og XJB Jernbanestasjonen og commuter lounge
Phasing - Phase Created: Som Bygget
Pset_WallCommon - LoadBearing: no; ExtendToStructure: no; Reference: 242_TC_22/100 GIPS-GIPS

# IfcWall: Basic Wall:V_Existing 200mm facade wood, Basic Wall:V_Existing 200mm facade wood:2241978
In: XX - C +15,37 TA E2
Type - PredefinedType: STANDARD; Material: Facade sketch 2 20 mm, Existing - Bridget key 180 mm
Type - Other - Category: Walls; Family Name: Basic Wall
Type - Construction - Function: Exterior; Width: 200 mm; Wrapping at Inserts: Do not wrap
Type - Graphics - Coarse Scale Fill Color: 0
Type - Identity Data - Type Name: V_Existing 200mm facade wood; Workset: Wall Types
Type - Materials and Finishes - Structural Material: Existing - Bridget key
Type - Analytical Properties - Roughness: 1; Absorptance: 0.1
Type - Pset_WallCommon - IsExternal: yes
Constraints - Location Line: Wall Centerline; Room Bounding: yes; Related to Mass: no; Base is Attached: no; Top is Attached: no; Base Constraint: XX - C +15,37 TA E2
Pset_ReinforcementBarPitchOfWall - Reference: V_Existing 200mm facade wood; sets with these values: 2
Pset_WallCommon - Reference: V_Existing 200mm facade wood; LoadBearing: no; ExtendToStructure: no
Cross-Section Definition - Cross-Section: Vertical
Structural - Structural Usage: Non-bearing; Structural: no
Identity Data - TA Workset: yes; Workset: XTA Terminal A
ePset_LocationTool - Splitting: RESULT
ePset_Simplebim - Assembly Level: Leaf
Other - Type: V_Existing 200mm facade wood; Family and Type: Basic Wall: V_Existing 200mm facade wood; Family: Basic Wall; Type Id: 3382455
Phasing - Phase Created: Som Bygget
Text - Code: E
ePset_SimplebimBasicQuantities - Area, side, gross, AABB (Simplebim): 22.2353 m2; Volume, net (Simplebim): 4.44731 m3; Thickness (Simplebim): 200 mm; Height (Simplebim): 4359 mm; Length (Simplebim): 5101 mm; Area, side, net, smaller (Simplebim): 22.2365 m2; Area, side, net, larger (Simplebim): 22.2365 m2; Area, side, gross, smaller (Simplebim): 22.2365 m2; Area, side, gross, larger (Simplebim): 22.2365 m2; Area, side, gross, average (Simplebim): 22.2365 m2; Area, largest surface, net (Simplebim): 22.2365 m2; Area, side, net, average (Simplebim): 22.2365 m2

# IfcWall: Basic Wall:V_Existing 300mm facade plate (3)
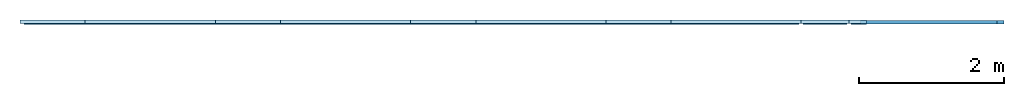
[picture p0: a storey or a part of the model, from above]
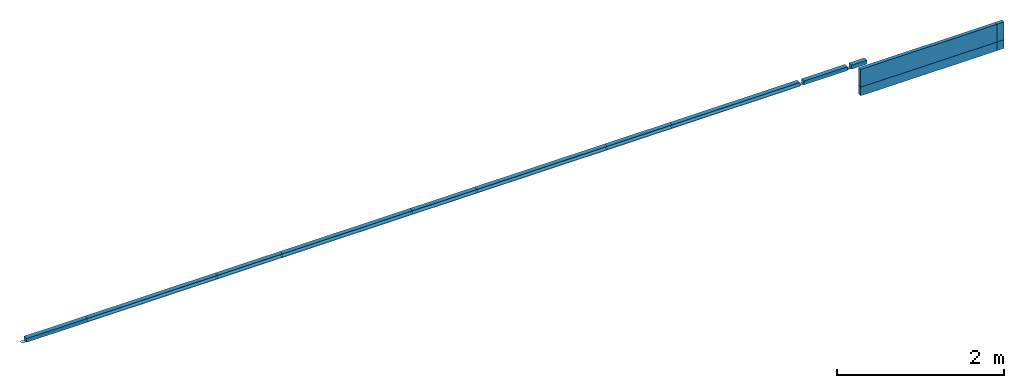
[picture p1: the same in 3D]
Properties of the parts of a building model (IFC2X3), part 2 of 2

# IfcWall: Basic Wall:V_Existing 300mm facade plate (3)
In: XX - C +15,37 TA E2
Type - PredefinedType: STANDARD; Material: Fasadeplate 8 mm, Existing - Bridget key 358 mm
Type - Other - Category: Walls; Family Name: Basic Wall
Type - Construction - Function: Exterior; Width: 366 mm; Wrapping at Inserts: Do not wrap
Type - Graphics - Coarse Scale Fill Color: 0
Type - Identity Data - Type Name: V_Existing 300mm facade plate; Workset: Wall Types
Type - Materials and Finishes - Structural Material: Existing - Bridget key
Type - Analytical Properties - Roughness: 1; Absorptance: 0.1
Type - Pset_WallCommon - IsExternal: yes
Constraints - Room Bounding: yes; Related to Mass: no; Base is Attached: no; Top is Attached: no; Base Constraint: XX - C +15,37 TA E2
Other - Family and Type: Basic Wall: V_Existing 300mm facade plate; Family: Basic Wall; Type Id: 18534855; Type: V_Existing 300mm facade plate
Cross-Section Definition - Cross-Section: Vertical
Structural - Structural Usage: Non-bearing; Structural: no
ePset_LocationTool - Splitting: RESULT
Pset_QuantityTakeOff - Reference: V_Existing 300mm facade plate; sets with these values: 2
ePset_Simplebim - Assembly Level: Leaf
Phasing - Phase Created: Som Bygget
Pset_WallCommon - LoadBearing: no; ExtendToStructure: no; Reference: V_Existing 300mm facade plate
ePset_SimplebimBasicQuantities - Thickness (Simplebim): 366 mm; Height (Simplebim): 4360 mm
Identity Data - Workset: XTB Terminal B
Name (Basic Wall:V_Existing 300mm facade plate:...) | Location Line | Area, side, gross, AABB (Simplebim) (m2) | Area, side, gross, average (Simplebim) (m2) = Area, side, net, average (Simplebim) (m2) | Volume, net (Simplebim) (m3) | Area, side, gross, smaller (Simplebim) (m2) = Area, side, net, smaller (Simplebim) (m2) | Area, side, net, larger (Simplebim) (m2) = Area, side, gross, larger (Simplebim) (m2) = Area, largest surface, net (Simplebim) (m2) | Length (Simplebim) (mm) | Code | TA Workset
18535364 | Finish Face: Interior | 22.6284 | 21.8319 | 7.99047 | 21.0341 | 22.6296 | 5190 | E | yes
18535363 | Finish Face: Interior | 9.156 | 9.156 | 1.42831 | 9.156 | 9.156 | 2100 | E | yes
18535389 | Finish Face: Exterior | 10.7997 | 10.0691 | 3.19577 | 9.33662 | 10.8017 | 2477

# IfcWall: Basic Wall:V_Existing 300mm facade wood, Basic Wall:V_Existing 300mm facade wood:18535387
In: XX - C +15,37 TA E2
Type - PredefinedType: STANDARD; Material: Facade sketch 2 20 mm, Existing - Bridget key 358 mm
Type - Other - Category: Walls; Family Name: Basic Wall
Type - Construction - Function: Exterior; Width: 378 mm; Wrapping at Inserts: Do not wrap
Type - Graphics - Coarse Scale Fill Color: 0
Type - Identity Data - Type Name: V_Existing 300mm facade wood; Workset: Wall Types
Type - Materials and Finishes - Structural Material: Existing - Bridget key
Type - Analytical Properties - Roughness: 1; Absorptance: 0.1
Type - Pset_WallCommon - IsExternal: yes
Constraints - Room Bounding: yes; Related to Mass: no; Base is Attached: no; Top is Attached: no; Location Line: Finish Face: Interior; Base Constraint: XX - C +15,37 TA E2
Pset_QuantityTakeOff - Reference: V_Existing 300mm facade wood; sets with these values: 2
Other - Type: V_Existing 300mm facade wood; Family: Basic Wall; Type Id: 18534853; Family and Type: Basic Wall: V_Existing 300mm facade wood
Cross-Section Definition - Cross-Section: Vertical
Structural - Structural Usage: Non-bearing; Structural: no
ePset_LocationTool - Splitting: RESULT
Identity Data - Workset: XTB Terminal B
ePset_Simplebim - Assembly Level: Leaf
ePset_SimplebimBasicQuantities - Area, side, net, larger (Simplebim): 38.3244 m2; Area, side, net, smaller (Simplebim): 38.3244 m2; Area, side, net, average (Simplebim): 38.3244 m2; Area, largest surface, net (Simplebim): 38.3244 m2; Area, side, gross, AABB (Simplebim): 38.3244 m2; Volume, net (Simplebim): 13.3918 m3; Thickness (Simplebim): 378 mm; Height (Simplebim): 4360 mm; Length (Simplebim): 8790 mm; Area, side, gross, larger (Simplebim): 41.5064 m2; Area, side, gross, smaller (Simplebim): 41.5064 m2; Area, side, gross, average (Simplebim): 41.5064 m2
Phasing - Phase Created: Som Bygget
Pset_WallCommon - Reference: V_Existing 300mm facade wood; LoadBearing: no; ExtendToStructure: no

# IfcWallStandardCase: Basic Wall:Generic-Innvendig-400mm, Basic Wall:Generic-Innvendig-400mm:18535416
In: XX - C +15,37 TA E2
Type - PredefinedType: STANDARD; Material: Default 400 mm
Type - Other - Category: Walls; Family Name: Basic Wall
Type - Construction - Function: Interior; Width: 400 mm; Wrapping at Inserts: Both
Type - Graphics - Coarse Scale Fill Color: 0
Type - Identity Data - Type Name: Generic-Innvendig-400mm; Workset: Wall Types
Type - Materials and Finishes - Structural Material: Default
Type - Analytical Properties - Roughness: 1; Absorptance: 0.1
Type - Pset_WallCommon - IsExternal: no
Constraints - Top Offset: -350 mm; Location Line: Finish Face: Exterior; Room Bounding: yes; Related to Mass: no; Base is Attached: no; Top is Attached: yes; Base Extension Distance: 0 mm; Base Offset: 0 mm; Top Extension Distance: 0 mm; Base Constraint: XX - C +15,37 TA E2; Unconnected Height: 2681.52 mm
Cross-Section Definition - Cross-Section: Vertical
Structural - Structural Usage: Non-bearing; Structural: no
Dimensions - Length: 4960.29 mm; Volume: 5.35378 m3; Area: 13.3845 m2
Identity Data - Workset: XTB Terminal B
ePset_Simplebim - Assembly Level: Leaf
Other - Type: Generic-Innvendig-400mm; Type Id: 18534861; Family: Basic Wall; Family and Type: Basic Wall: Generic-Innvendig-400mm
Pset_WallCommon - Reference: Generic-Innvendig-400mm; LoadBearing: no; ExtendToStructure: yes
Pset_QuantityTakeOff - Reference: Generic-Innvendig-400mm; sets with these values: 2
ePset_LocationTool - Splitting: ORIGINAL
Phasing - Phase Created: Som Bygget
ePset_SimplebimBasicQuantities - Height (Simplebim): 2778.57 mm; Length (Simplebim): 4960.29 mm; Volume, net (Simplebim): 5.35378 m3; Area, side, gross, AABB (Simplebim): 13.7825 m2; Thickness (Simplebim): 400 mm; Area, side, gross, smaller (Simplebim): 13.3845 m2; Area, side, net, smaller (Simplebim): 13.3845 m2; Area, side, gross, average (Simplebim): 13.3845 m2; Area, side, net, average (Simplebim): 13.3845 m2; Area, largest surface, net (Simplebim): 13.3845 m2; Area, side, gross, larger (Simplebim): 13.3845 m2; Area, side, net, larger (Simplebim): 13.3845 m2

# IfcWallStandardCase: Basic Wall:V_Existing 100mm (4)
In: XX - C +15,37 TA E2
Type - PredefinedType: STANDARD; Material: Existing - Bridget key 100 mm
Type - Other - Category: Walls; Family Name: Basic Wall
Type - Construction - Function: Interior; Width: 100 mm; Wrapping at Inserts: Both
Type - Graphics - Coarse Scale Fill Color: 0
Type - Identity Data - Type Name: V_Existing 100mm; Workset: Wall Types
Type - Materials and Finishes - Structural Material: Existing - Bridget key
Type - Analytical Properties - Roughness: 1; Absorptance: 0.1
Type - Pset_WallCommon - IsExternal: no
Type - Text - Core Kode: EKS; Vegg Kode: EKS
Other - Type: V_Existing 100mm; Family: Basic Wall; Type Id: 204692; Family and Type: Basic Wall: V_Existing 100mm
Cross-Section Definition - Cross-Section: Vertical
Structural - Structural Usage: Non-bearing; Structural: no
Pset_WallCommon - Reference: V_Existing 100mm; LoadBearing: no; ExtendToStructure: no
Identity Data - Workset: XTB Terminal B
Pset_ReinforcementBarPitchOfWall - Reference: V_Existing 100mm; sets with these values: 2
Constraints - Base Extension Distance: -530 mm; Base Offset: -1205 mm; Location Line: Finish Face: Exterior; Room Bounding: yes; Related to Mass: no; Base is Attached: no; Top is Attached: no; Top Extension Distance: 0 mm; Base Constraint: XX - C +15,37 TA E2; Top Offset: 70 mm; Unconnected Height: 4565 mm
ePset_Simplebim - Assembly Level: Leaf
ePset_LocationTool - Splitting: ORIGINAL
Phasing - Phase Created: Som Bygget
ePset_SimplebimBasicQuantities - Thickness (Simplebim): 100 mm; Height (Simplebim): 4565 mm
Dimensions - Length: 600 mm
Name (Basic Wall:V_Existing 100mm:...) | Area, side, gross, AABB (Simplebim) (m2) = Area, side, gross, average (Simplebim) (m2) = Area, largest surface, net (Simplebim) (m2) = Area, side, net, average (Simplebim) (m2) = Area, side, net, smaller (Simplebim) (m2) = Area, side, net, larger (Simplebim) (m2) = Area, side, gross, smaller (Simplebim) (m2) = Area, side, gross, larger (Simplebim) (m2) = Area (m2) | Volume, net (Simplebim) (m3) = Volume (m3) | Length (Simplebim) (mm)
18535412 | 2.739 | 0.2739 | 600
18535413 | 2.739 | 0.2739 | 600
18535414 | 3.1955 | 0.31955 | 700
18535415 | 2.2825 | 0.22825 | 500

# IfcWallStandardCase: Basic Wall:V_Existing 10mm Pir Wood Panel, Basic Wall:V_Existing 10mm Pir Wood Panel:18535362
In: XX - C +15,37 TA E2
Type - PredefinedType: STANDARD; Material: Værnes_Tre panel Existing 10 mm
Type - Other - Category: Walls; Family Name: Basic Wall
Type - Construction - Function: Interior; Width: 10 mm; Wrapping at Inserts: Both
Type - Graphics - Coarse Scale Fill Color: 0
Type - Identity Data - Type Name: V_Existing 10mm Pir Wood Panel; Workset: Wall Types
Type - Materials and Finishes - Structural Material: Værnes_Tre panel Existing
Type - Analytical Properties - Roughness: 1; Absorptance: 0.1
Type - Pset_WallCommon - IsExternal: no
Dimensions - Length: 13555 mm; Area: 9.49162 m2; Volume: 0.0949162 m3
Cross-Section Definition - Cross-Section: Vertical
Other - Family: Basic Wall; Type Id: 9763589; Type: V_Existing 10mm Pir Wood Panel; Family and Type: Basic Wall: V_Existing 10mm Pir Wood Panel
Visibility - N/R BIM do not use: yes
Structural - Structural Usage: Non-bearing; Structural: no
Constraints - Base Offset: 2677.41 mm; Top Offset: 127.644 mm; Top Constraint: Up to level: XX - C +18,62; Room Bounding: yes; Related to Mass: no; Base is Attached: no; Top is Attached: no; Base Extension Distance: 0 mm; Top Extension Distance: 0 mm; Location Line: Finish Face: Interior; Base Constraint: XX - C +15,37 TA E2; Unconnected Height: 700.231 mm
Pset_QuantityTakeOff - Reference: V_Existing 10mm Pir Wood Panel; sets with these values: 2
ePset_SimplebimBasicQuantities - Length (Simplebim): 13555 mm; Thickness (Simplebim): 10 mm; Area, side, gross, AABB (Simplebim): 9.49162 m2; Area, side, net, smaller (Simplebim): 9.49163 m2; Area, side, net, larger (Simplebim): 9.49163 m2; Area, side, gross, smaller (Simplebim): 9.49163 m2; Area, side, gross, larger (Simplebim): 9.49163 m2; Area, side, gross, average (Simplebim): 9.49163 m2; Area, largest surface, net (Simplebim): 9.49163 m2; Area, side, net, average (Simplebim): 9.49163 m2; Volume, net (Simplebim): 0.0949162 m3; Height (Simplebim): 700.231 mm
ePset_Simplebim - Assembly Level: Leaf
Pset_WallCommon - LoadBearing: no; ExtendToStructure: no; Reference: V_Existing 10mm Pir Wood Panel
Phasing - Phase Created: Som Bygget
ePset_LocationTool - Splitting: ORIGINAL
Identity Data - TA Workset: yes; Workset: XTB Terminal B

# IfcWallStandardCase: Basic Wall:V_Existing 400mm, Basic Wall:V_Existing 400mm:18535351
In: XX - C +18,62
Type - PredefinedType: STANDARD; Material: Existing - Bridget key 400 mm
Type - Other - Category: Walls; Family Name: Basic Wall
Type - Construction - Function: Exterior; Width: 400 mm; Wrapping at Inserts: Do not wrap
Type - Graphics - Coarse Scale Fill Color: 0
Type - Identity Data - Type Name: V_Existing 400mm; Workset: Wall Types
Type - Materials and Finishes - Structural Material: Existing - Bridget key
Type - Analytical Properties - Roughness: 1; Absorptance: 0.1
Type - Pset_WallCommon - IsExternal: yes
Pset_QuantityTakeOff - Reference: V_Existing 400mm; sets with these values: 2
Other - Family: Basic Wall; Type Id: 4521273; Family and Type: Basic Wall: V_Existing 400mm; Type: V_Existing 400mm
Cross-Section Definition - Cross-Section: Vertical
ePset_LocationTool - Splitting: ORIGINAL
Structural - Structural Usage: Non-bearing; Structural: no
ePset_Simplebim - Assembly Level: Leaf
Pset_WallCommon - LoadBearing: no; ExtendToStructure: no; Reference: V_Existing 400mm
Constraints - Unconnected Height: 3372.64 mm; Top Offset: -328.864 mm; Location Line: Wall Centerline; Base Constraint: XX - C +18,62; Room Bounding: yes; Related to Mass: no; Base is Attached: no; Top is Attached: no; Base Extension Distance: 0 mm; Top Extension Distance: 0 mm; Base Offset: -3250 mm
Phasing - Phase Created: Som Bygget
ePset_SimplebimBasicQuantities - Volume, net (Simplebim): 3.7442 m3; Area, side, gross, average (Simplebim): 9.36051 m2; Area, largest surface, net (Simplebim): 9.36051 m2; Area, side, net, average (Simplebim): 9.36051 m2; Area, side, net, smaller (Simplebim): 9.36051 m2; Area, side, net, larger (Simplebim): 9.36051 m2; Area, side, gross, smaller (Simplebim): 9.36051 m2; Area, side, gross, larger (Simplebim): 9.36051 m2; Area, side, gross, AABB (Simplebim): 9.36051 m2; Height (Simplebim): 696.126 mm; Length (Simplebim): 13446.6 mm; Thickness (Simplebim): 400 mm
Dimensions - Volume: 3.7442 m3; Area: 9.36051 m2; Length: 13546.6 mm
Identity Data - TA Workset: yes; Workset: XTB Terminal B
